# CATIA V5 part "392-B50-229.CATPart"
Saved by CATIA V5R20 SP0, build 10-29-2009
Part number: 392-B50-229
Definition: NONE
Nomenclature: 392-B50-229
Source: Unknown
Description: 392-B50-229
Bounding box of the stored display mesh (mm): x 0 to 229, y -24.562 to 24.562, z -24.4 to 24.222
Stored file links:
  C:\Users\Utente\Desktop\IO LAVORO\3D X SITO CF\X SITO\3D files 392B\392-B50-229.CATPart

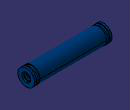
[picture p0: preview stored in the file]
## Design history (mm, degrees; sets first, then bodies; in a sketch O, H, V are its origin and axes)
Body1 "392-B50-229" (main body)
  Solid1: solid without history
